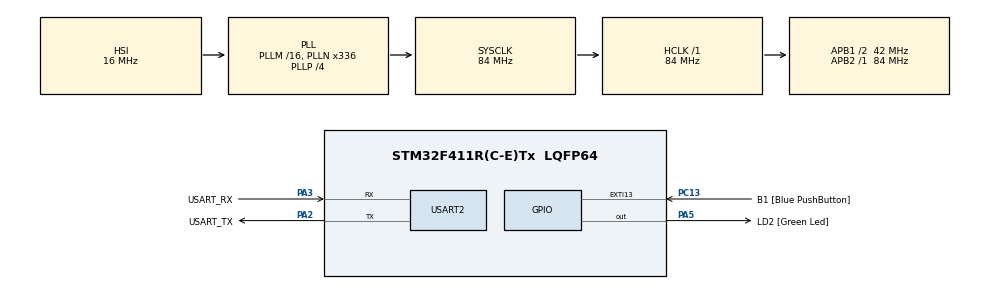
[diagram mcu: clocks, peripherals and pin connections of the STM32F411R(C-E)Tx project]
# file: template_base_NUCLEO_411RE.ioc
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Mcu.Family=STM32F4
Mcu.Name=STM32F411R(C-E)Tx
Mcu.Package=LQFP64
NVIC.PriorityGroup=NVIC_PRIORITYGROUP_4
NVIC.USART2_IRQn=true\:0\:0\:false\:false\:true\:true
PA13.GPIO_Label=TMS
PA13.Mode=Serial_Wire
PA13.Signal=SYS_JTMS-SWDIO
PA14.GPIO_Label=TCK
PA14.Mode=Serial_Wire
PA14.Signal=SYS_JTCK-SWCLK
PA2.GPIO_Label=USART_TX
PA2.Mode=Asynchronous
PA2.Signal=USART2_TX
PA3.GPIO_Label=USART_RX
PA3.Mode=Asynchronous
PA3.Signal=USART2_RX
PA5.GPIO_Label=LD2 [Green Led]
PA5.Signal=GPIO_Output
PB3.GPIO_Label=SWO
PB3.Signal=SYS_JTDO-SWO
PC13-ANTI_TAMP.GPIO_Label=B1 [Blue PushButton]
PC13-ANTI_TAMP.GPIO_ModeDefaultEXTI=GPIO_MODE_IT_FALLING
PC13-ANTI_TAMP.Signal=GPXTI13
PC14-OSC32_IN.Mode=LSE-External-Oscillator
PC14-OSC32_IN.Signal=RCC_OSC32_IN
PC15-OSC32_OUT.Mode=LSE-External-Oscillator
PC15-OSC32_OUT.Signal=RCC_OSC32_OUT
PH0\ -\ OSC_IN.Mode=HSE-External-Clock-Source
PH0\ -\ OSC_IN.Signal=RCC_OSC_IN
PH1\ -\ OSC_OUT.Mode=HSE-External-Clock-Source
PH1\ -\ OSC_OUT.Signal=RCC_OSC_OUT
ProjectManager.HeapSize=0x200
ProjectManager.StackSize=0x400
ProjectManager.TargetToolchain=TrueSTUDIO
RCC.48MHZClocksFreq_Value=84000000
RCC.AHBFreq_Value=84000000
RCC.APB1CLKDivider=RCC_HCLK_DIV2
RCC.APB1Freq_Value=42000000
RCC.APB1TimFreq_Value=84000000
RCC.APB2Freq_Value=84000000
RCC.APB2TimFreq_Value=84000000
RCC.CortexFreq_Value=84000000
RCC.FLatency-AdvancedSettings=FLASH_LATENCY_2
RCC.HCLKFreq_Value=84000000
RCC.HSE_VALUE=8000000
RCC.HSI_VALUE=16000000
RCC.PLLN=336
RCC.PLLP=RCC_PLLP_DIV4
RCC.SYSCLKFreq_VALUE=84000000
RCC.SYSCLKSource=RCC_SYSCLKSOURCE_PLLCLK
RCC.VCOOutputFreq_Value=336000000
USART2.VirtualMode=VM_ASYNC
VP_CRC_VS_CRC.Mode=CRC_Activate
board=NUCLEO-F411RE

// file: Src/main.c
/**
  ******************************************************************************
  * @file           : main.c
  * @brief          : Main program body
  ******************************************************************************
  ** This notice applies to any and all portions of this file
  * that are not between comment pairs USER CODE BEGIN and
  * USER CODE END. Other portions of this file, whether
  * inserted by the user or by software development tools
  * are owned by their respective copyright owners.
  *
  * COPYRIGHT(c) 2019 STMicroelectronics
  *
  * Redistribution and use in source and binary forms, with or without modification,
  * are permitted provided that the following conditions are met:
  *   1. Redistributions of source code must retain the above copyright notice,
  *      this list of conditions and the following disclaimer.
  *   2. Redistributions in binary form must reproduce the above copyright notice,
  *      this list of conditions and the following disclaimer in the documentation
  *      and/or other materials provided with the distribution.
  *   3. Neither the name of STMicroelectronics nor the names of its contributors
  *      may be used to endorse or promote products derived from this software
  *      without specific prior written permission.
  *
  * THIS SOFTWARE IS PROVIDED BY THE COPYRIGHT HOLDERS AND CONTRIBUTORS "AS IS"
  * AND ANY EXPRESS OR IMPLIED WARRANTIES, INCLUDING, BUT NOT LIMITED TO, THE
  * IMPLIED WARRANTIES OF MERCHANTABILITY AND FITNESS FOR A PARTICULAR PURPOSE ARE
  * DISCLAIMED. IN NO EVENT SHALL THE COPYRIGHT HOLDER OR CONTRIBUTORS BE LIABLE
  * FOR ANY DIRECT, INDIRECT, INCIDENTAL, SPECIAL, EXEMPLARY, OR CONSEQUENTIAL
  * DAMAGES (INCLUDING, BUT NOT LIMITED TO, PROCUREMENT OF SUBSTITUTE GOODS OR
  * SERVICES; LOSS OF USE, DATA, OR PROFITS; OR BUSINESS INTERRUPTION) HOWEVER
  * CAUSED AND ON ANY THEORY OF LIABILITY, WHETHER IN CONTRACT, STRICT LIABILITY,
  * OR TORT (INCLUDING NEGLIGENCE OR OTHERWISE) ARISING IN ANY WAY OUT OF THE USE
  * OF THIS SOFTWARE, EVEN IF ADVISED OF THE POSSIBILITY OF SUCH DAMAGE.
  *
  ******************************************************************************
  */
#include "main.h"
#include "stm32f4xx_hal.h"

CRC_HandleTypeDef hcrc;

UART_HandleTypeDef huart2;

/* USER CODE BEGIN PV */
/* Private variables ---------------------------------------------------------*/

/* USER CODE END PV */

void SystemClock_Config(void);
static void MX_GPIO_Init(void);
static void MX_USART2_UART_Init(void);
static void MX_CRC_Init(void);

/* USER CODE BEGIN PFP */
/* Private function prototypes -----------------------------------------------*/

/* USER CODE END PFP */

int main(void)
{

  /* MCU Configuration----------------------------------------------------------*/

  /* Reset of all peripherals, Initializes the Flash interface and the Systick. */
  HAL_Init();

  /* Configure the system clock */
  SystemClock_Config();

  /* Initialize all configured peripherals */
  MX_GPIO_Init();
  MX_USART2_UART_Init();
  MX_CRC_Init();

  /* Infinite loop */
  while(1){
	  HAL_GPIO_WritePin(RGB_GPIO_Port,R_Pin,GPIO_PIN_SET);
	  HAL_Delay(500);
	  HAL_GPIO_WritePin(RGB_GPIO_Port,G_Pin,GPIO_PIN_SET);
	  HAL_Delay(500);
	  HAL_GPIO_WritePin(RGB_GPIO_Port,B_Pin,GPIO_PIN_SET);
	  HAL_Delay(500);
	  HAL_GPIO_WritePin(RGB_GPIO_Port,R_Pin,GPIO_PIN_RESET);
	  HAL_Delay(500);
	  HAL_GPIO_WritePin(RGB_GPIO_Port,G_Pin,GPIO_PIN_RESET);
	  HAL_Delay(500);
	  HAL_GPIO_WritePin(RGB_GPIO_Port,B_Pin,GPIO_PIN_RESET);
	  HAL_Delay(500);

  }
}

void SystemClock_Config(void)
{

  RCC_OscInitTypeDef RCC_OscInitStruct;
  RCC_ClkInitTypeDef RCC_ClkInitStruct;

    /**Configure the main internal regulator output voltage
    */
  __HAL_RCC_PWR_CLK_ENABLE();

  __HAL_PWR_VOLTAGESCALING_CONFIG(PWR_REGULATOR_VOLTAGE_SCALE1);

    /**Initializes the CPU, AHB and APB busses clocks
    */
  RCC_OscInitStruct.OscillatorType = RCC_OSCILLATORTYPE_HSI;
  RCC_OscInitStruct.HSIState = RCC_HSI_ON;
  RCC_OscInitStruct.HSICalibrationValue = 16;
  RCC_OscInitStruct.PLL.PLLState = RCC_PLL_ON;
  RCC_OscInitStruct.PLL.PLLSource = RCC_PLLSOURCE_HSI;
  RCC_OscInitStruct.PLL.PLLM = 16;
  RCC_OscInitStruct.PLL.PLLN = 336;
  RCC_OscInitStruct.PLL.PLLP = RCC_PLLP_DIV4;
  RCC_OscInitStruct.PLL.PLLQ = 4;
  if (HAL_RCC_OscConfig(&RCC_OscInitStruct) != HAL_OK)
  {
    _Error_Handler(__FILE__, __LINE__);
  }

    /**Initializes the CPU, AHB and APB busses clocks
    */
  RCC_ClkInitStruct.ClockType = RCC_CLOCKTYPE_HCLK|RCC_CLOCKTYPE_SYSCLK
                              |RCC_CLOCKTYPE_PCLK1|RCC_CLOCKTYPE_PCLK2;
  RCC_ClkInitStruct.SYSCLKSource = RCC_SYSCLKSOURCE_PLLCLK;
  RCC_ClkInitStruct.AHBCLKDivider = RCC_SYSCLK_DIV1;
  RCC_ClkInitStruct.APB1CLKDivider = RCC_HCLK_DIV2;
  RCC_ClkInitStruct.APB2CLKDivider = RCC_HCLK_DIV1;

  if (HAL_RCC_ClockConfig(&RCC_ClkInitStruct, FLASH_LATENCY_2) != HAL_OK)
  {
    _Error_Handler(__FILE__, __LINE__);
  }

    /**Configure the Systick interrupt time
    */
  HAL_SYSTICK_Config(HAL_RCC_GetHCLKFreq()/1000);

    /**Configure the Systick
    */
  HAL_SYSTICK_CLKSourceConfig(SYSTICK_CLKSOURCE_HCLK);

  /* SysTick_IRQn interrupt configuration */
  HAL_NVIC_SetPriority(SysTick_IRQn, 0, 0);
}

/* CRC init function */
static void MX_CRC_Init(void)
{

  hcrc.Instance = CRC;
  if (HAL_CRC_Init(&hcrc) != HAL_OK)
  {
    _Error_Handler(__FILE__, __LINE__);
  }

}

/* USART2 init function */
static void MX_USART2_UART_Init(void)
{

  huart2.Instance = USART2;
  huart2.Init.BaudRate = 115200;
  huart2.Init.WordLength = UART_WORDLENGTH_8B;
  huart2.Init.StopBits = UART_STOPBITS_1;
  huart2.Init.Parity = UART_PARITY_NONE;
  huart2.Init.Mode = UART_MODE_TX_RX;
  huart2.Init.HwFlowCtl = UART_HWCONTROL_NONE;
  huart2.Init.OverSampling = UART_OVERSAMPLING_16;
  if (HAL_UART_Init(&huart2) != HAL_OK)
  {
    _Error_Handler(__FILE__, __LINE__);
  }

}

/** Configure pins as
        * Analog
        * Input
        * Output
        * EVENT_OUT
        * EXTI
*/
static void MX_GPIO_Init(void)
{

  GPIO_InitTypeDef GPIO_InitStruct;

  /* GPIO Ports Clock Enable */
  __HAL_RCC_GPIOC_CLK_ENABLE();
  __HAL_RCC_GPIOH_CLK_ENABLE();
  __HAL_RCC_GPIOA_CLK_ENABLE();
  __HAL_RCC_GPIOB_CLK_ENABLE();

  /*Configure GPIO pin Output Level */
  HAL_GPIO_WritePin(LD2_GPIO_Port, LD2_Pin, GPIO_PIN_RESET);

  /*Configure GPIO pin : B1_Pin */
  GPIO_InitStruct.Pin = B1_Pin;
  GPIO_InitStruct.Mode = GPIO_MODE_IT_FALLING;
  GPIO_InitStruct.Pull = GPIO_NOPULL;
  HAL_GPIO_Init(B1_GPIO_Port, &GPIO_InitStruct);

  /*Configure GPIO pin : LD2_Pin */
  GPIO_InitStruct.Pin = LD2_Pin;
  GPIO_InitStruct.Mode = GPIO_MODE_OUTPUT_PP;
  GPIO_InitStruct.Pull = GPIO_NOPULL;
  GPIO_InitStruct.Speed = GPIO_SPEED_FREQ_LOW;
  HAL_GPIO_Init(LD2_GPIO_Port, &GPIO_InitStruct);

  /*Configure GPIO pin : R_Pin */
  GPIO_InitStruct.Pin = R_Pin;
  GPIO_InitStruct.Mode = GPIO_MODE_OUTPUT_PP;
  GPIO_InitStruct.Pull = GPIO_NOPULL;
  GPIO_InitStruct.Speed = GPIO_SPEED_FREQ_LOW;
  HAL_GPIO_Init(RGB_GPIO_Port, &GPIO_InitStruct);
  /*Configure GPIO pin : G_Pin */
  GPIO_InitStruct.Pin = G_Pin;
  GPIO_InitStruct.Mode = GPIO_MODE_OUTPUT_PP;
  GPIO_InitStruct.Pull = GPIO_NOPULL;
  GPIO_InitStruct.Speed = GPIO_SPEED_FREQ_LOW;
  HAL_GPIO_Init(RGB_GPIO_Port, &GPIO_InitStruct);
  /*Configure GPIO pin : B_Pin */
  GPIO_InitStruct.Pin = B_Pin;
  GPIO_InitStruct.Mode = GPIO_MODE_OUTPUT_PP;
  GPIO_InitStruct.Pull = GPIO_NOPULL;
  GPIO_InitStruct.Speed = GPIO_SPEED_FREQ_LOW;
  HAL_GPIO_Init(RGB_GPIO_Port, &GPIO_InitStruct);

}

void _Error_Handler(char *file, int line)
{
  while(1)
  {
  }
}

/************************ (C) COPYRIGHT STMicroelectronics *****END OF FILE****/
